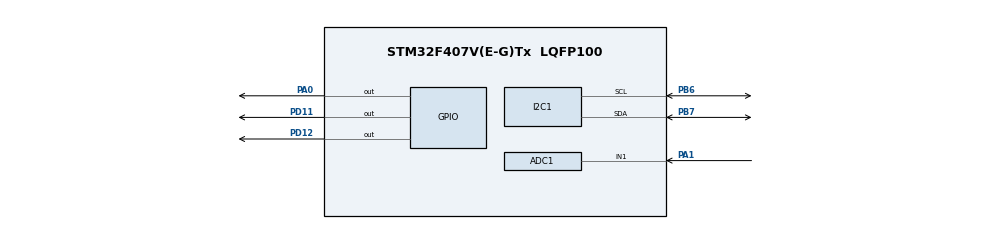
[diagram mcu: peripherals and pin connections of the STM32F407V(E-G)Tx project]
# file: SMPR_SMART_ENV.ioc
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ADC1.Channel-0\#ChannelRegularConversion=ADC_CHANNEL_1
ADC1.NbrOfConversionFlag=1
ADC1.Rank-0\#ChannelRegularConversion=1
ADC1.SamplingTime-0\#ChannelRegularConversion=ADC_SAMPLETIME_3CYCLES
ADC1.master=1
Mcu.Family=STM32F4
Mcu.Name=STM32F407V(E-G)Tx
Mcu.Package=LQFP100
NVIC.ADC_IRQn=true\:0\:0\:false\:false\:true\:true\:true\:true
NVIC.PriorityGroup=NVIC_PRIORITYGROUP_0
PA0-WKUP.PinState=GPIO_PIN_RESET
PA0-WKUP.Signal=GPIO_Output
PA1.Signal=ADCx_IN1
PB6.Mode=I2C
PB6.Signal=I2C1_SCL
PB7.Mode=I2C
PB7.Signal=I2C1_SDA
PD11.PinState=GPIO_PIN_RESET
PD11.Signal=GPIO_Output
PD12.Signal=GPIO_Output
PH0-OSC_IN.Mode=HSE-External-Oscillator
PH0-OSC_IN.Signal=RCC_OSC_IN
PH1-OSC_OUT.Mode=HSE-External-Oscillator
PH1-OSC_OUT.Signal=RCC_OSC_OUT
ProjectManager.HeapSize=0x200
ProjectManager.StackSize=0x400
ProjectManager.TargetToolchain=STM32CubeIDE
RCC.48MHZClocksFreq_Value=14285714.285714285
RCC.AHBFreq_Value=25000000
RCC.APB1CLKDivider=RCC_HCLK_DIV4
RCC.APB1Freq_Value=6250000
RCC.APB1TimFreq_Value=12500000
RCC.APB2CLKDivider=RCC_HCLK_DIV2
RCC.APB2Freq_Value=12500000
RCC.APB2TimFreq_Value=25000000
RCC.CortexFreq_Value=25000000
RCC.HCLKFreq_Value=25000000
RCC.HSE_VALUE=8000000
RCC.HSI_VALUE=16000000
RCC.LSE_VALUE=32768
RCC.PLLM=8
RCC.PLLN=50
RCC.PLLP=RCC_PLLP_DIV4
RCC.PLLQ=7
RCC.SYSCLKFreq_VALUE=25000000
RCC.SYSCLKSource=RCC_SYSCLKSOURCE_PLLCLK
RCC.VCOOutputFreq_Value=100000000
SH.ADCx_IN1.0=ADC1_IN1,IN1
board=STM32F407G-DISC1

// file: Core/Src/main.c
/* USER CODE BEGIN Header */
/**
  ******************************************************************************
  * @file           : main.c
  * @brief          : Main program body
  ******************************************************************************
  * @attention
  *
  * Copyright (c) 2025 STMicroelectronics.
  * All rights reserved.
  *
  * This software is licensed under terms that can be found in the LICENSE file
  * in the root directory of this software component.
  * If no LICENSE file comes with this software, it is provided AS-IS.
  *
  ******************************************************************************
  */
/* USER CODE END Header */
#include "main.h"
#include<string.h>
#include<stdio.h>
#include"DHT11.h"
#include"MQ2.h"
#include"MY_LCD.h"

ADC_HandleTypeDef hadc1;

I2C_HandleTypeDef hi2c1;

void SystemClock_Config(void);
static void MX_GPIO_Init(void);
static void MX_ADC1_Init(void);
static void MX_I2C1_Init(void);

int main(void)
{

  /* USER CODE BEGIN 1 */
	uint8_t temp = 0;
	uint8_t hum = 0;

  /* USER CODE END 1 */

  /* MCU Configuration--------------------------------------------------------*/

  /* Reset of all peripherals, Initializes the Flash interface and the Systick. */
  HAL_Init();

  /* USER CODE BEGIN Init */
 // DHT11_Init();

  /* USER CODE END Init */

  /* Configure the system clock */
  SystemClock_Config();

  /* Initialize all configured peripherals */
  MX_GPIO_Init();
  MX_ADC1_Init();
  MX_I2C1_Init();
  /* USER CODE BEGIN 2 */
  DHT11_Init();
  char str1[60];
  char str2[50];
  int gas;
  if (!lcd16x2_i2c_init(&hi2c1))
  {
	  while(1);
  }

  /* USER CODE END 2 */

  /* Infinite loop */
  while (1)
  {
	  gas=mq2_Read();
	  lcd16x2_i2c_clear();
	  lcd16x2_i2c_setCursor(0,0);
	  lcd16x2_i2c_printf("SmokeD:");
	  lcd16x2_i2c_setCursor(0,8);
	  sprintf(str1, "ADC:%d",gas);
	  lcd16x2_i2c_printf(str1);
	  HAL_Delay(500);

	  HAL_GPIO_WritePin(GPIOD,GPIO_PIN_11|GPIO_PIN_12,GPIO_PIN_RESET);
	  if(gas>200 && gas<500)
	  {
		  HAL_GPIO_WritePin(GPIOD,GPIO_PIN_11,GPIO_PIN_SET);
	  }
	  else if(gas>500 && gas<2000)
	  {
		  HAL_GPIO_WritePin(GPIOD, GPIO_PIN_12,GPIO_PIN_SET);
	  }
	  if (DHT11_Read(&temp,&hum)==0)
	  	  {
	  		  lcd16x2_i2c_clear();
	  		 // lcd16x2_i2c_setCursor(1,0);
	  		 // lcd16x2_i2c_printf("DHT11:");
	  		  lcd16x2_i2c_setCursor(1,0);
	  		  sprintf(str2,"T:=%d c,H:=%d ",temp,hum);
	  		  lcd16x2_i2c_printf(str2);
	  		  HAL_Delay(500);
	  	  }

  }
}

void SystemClock_Config(void)
{
  RCC_OscInitTypeDef RCC_OscInitStruct = {0};
  RCC_ClkInitTypeDef RCC_ClkInitStruct = {0};

  /** Configure the main internal regulator output voltage
  */
  __HAL_RCC_PWR_CLK_ENABLE();
  __HAL_PWR_VOLTAGESCALING_CONFIG(PWR_REGULATOR_VOLTAGE_SCALE1);

  /** Initializes the RCC Oscillators according to the specified parameters
  * in the RCC_OscInitTypeDef structure.
  */
  RCC_OscInitStruct.OscillatorType = RCC_OSCILLATORTYPE_HSE;
  RCC_OscInitStruct.HSEState = RCC_HSE_ON;
  RCC_OscInitStruct.PLL.PLLState = RCC_PLL_ON;
  RCC_OscInitStruct.PLL.PLLSource = RCC_PLLSOURCE_HSE;
  RCC_OscInitStruct.PLL.PLLM = 8;
  RCC_OscInitStruct.PLL.PLLN = 336;
  RCC_OscInitStruct.PLL.PLLP = RCC_PLLP_DIV2;
  RCC_OscInitStruct.PLL.PLLQ = 7;
  if (HAL_RCC_OscConfig(&RCC_OscInitStruct) != HAL_OK)
  {
    Error_Handler();
  }

  /** Initializes the CPU, AHB and APB buses clocks
  */
  RCC_ClkInitStruct.ClockType = RCC_CLOCKTYPE_HCLK|RCC_CLOCKTYPE_SYSCLK
                              |RCC_CLOCKTYPE_PCLK1|RCC_CLOCKTYPE_PCLK2;
  RCC_ClkInitStruct.SYSCLKSource = RCC_SYSCLKSOURCE_PLLCLK;
  RCC_ClkInitStruct.AHBCLKDivider = RCC_SYSCLK_DIV1;
  RCC_ClkInitStruct.APB1CLKDivider = RCC_HCLK_DIV4;
  RCC_ClkInitStruct.APB2CLKDivider = RCC_HCLK_DIV2;

  if (HAL_RCC_ClockConfig(&RCC_ClkInitStruct, FLASH_LATENCY_5) != HAL_OK)
  {
    Error_Handler();
  }
}

static void MX_ADC1_Init(void)
{

  ADC_ChannelConfTypeDef sConfig = {0};

  /** Configure the global features of the ADC (Clock, Resolution, Data Alignment and number of conversion)
  */
  hadc1.Instance = ADC1;
  hadc1.Init.ClockPrescaler = ADC_CLOCK_SYNC_PCLK_DIV4;
  hadc1.Init.Resolution = ADC_RESOLUTION_12B;
  hadc1.Init.ScanConvMode = DISABLE;
  hadc1.Init.ContinuousConvMode = DISABLE;
  hadc1.Init.DiscontinuousConvMode = DISABLE;
  hadc1.Init.ExternalTrigConvEdge = ADC_EXTERNALTRIGCONVEDGE_NONE;
  hadc1.Init.ExternalTrigConv = ADC_SOFTWARE_START;
  hadc1.Init.DataAlign = ADC_DATAALIGN_RIGHT;
  hadc1.Init.NbrOfConversion = 1;
  hadc1.Init.DMAContinuousRequests = DISABLE;
  hadc1.Init.EOCSelection = ADC_EOC_SINGLE_CONV;
  if (HAL_ADC_Init(&hadc1) != HAL_OK)
  {
    Error_Handler();
  }

  /** Configure for the selected ADC regular channel its corresponding rank in the sequencer and its sample time.
  */
  sConfig.Channel = ADC_CHANNEL_1;
  sConfig.Rank = 1;
  sConfig.SamplingTime = ADC_SAMPLETIME_3CYCLES;
  if (HAL_ADC_ConfigChannel(&hadc1, &sConfig) != HAL_OK)
  {
    Error_Handler();
  }

}

static void MX_I2C1_Init(void)
{

  hi2c1.Instance = I2C1;
  hi2c1.Init.ClockSpeed = 100000;
  hi2c1.Init.DutyCycle = I2C_DUTYCYCLE_2;
  hi2c1.Init.OwnAddress1 = 0;
  hi2c1.Init.AddressingMode = I2C_ADDRESSINGMODE_7BIT;
  hi2c1.Init.DualAddressMode = I2C_DUALADDRESS_DISABLE;
  hi2c1.Init.OwnAddress2 = 0;
  hi2c1.Init.GeneralCallMode = I2C_GENERALCALL_DISABLE;
  hi2c1.Init.NoStretchMode = I2C_NOSTRETCH_DISABLE;
  if (HAL_I2C_Init(&hi2c1) != HAL_OK)
  {
    Error_Handler();
  }

}

static void MX_GPIO_Init(void)
{
  GPIO_InitTypeDef GPIO_InitStruct = {0};

  /* GPIO Ports Clock Enable */
  __HAL_RCC_GPIOH_CLK_ENABLE();
  __HAL_RCC_GPIOA_CLK_ENABLE();
  __HAL_RCC_GPIOD_CLK_ENABLE();
  __HAL_RCC_GPIOB_CLK_ENABLE();

  /*Configure GPIO pin Output Level */
  HAL_GPIO_WritePin(GPIOA, GPIO_PIN_0, GPIO_PIN_RESET);

  /*Configure GPIO pin Output Level */
  HAL_GPIO_WritePin(GPIOD, GPIO_PIN_11|GPIO_PIN_12, GPIO_PIN_RESET);

  /*Configure GPIO pin : PA0 */
  GPIO_InitStruct.Pin = GPIO_PIN_0;
  GPIO_InitStruct.Mode = GPIO_MODE_OUTPUT_PP;
  GPIO_InitStruct.Pull = GPIO_NOPULL;
  GPIO_InitStruct.Speed = GPIO_SPEED_FREQ_LOW;
  HAL_GPIO_Init(GPIOA, &GPIO_InitStruct);

  /*Configure GPIO pins : PD11 PD12 */
  GPIO_InitStruct.Pin = GPIO_PIN_11|GPIO_PIN_12;
  GPIO_InitStruct.Mode = GPIO_MODE_OUTPUT_PP;
  GPIO_InitStruct.Pull = GPIO_NOPULL;
  GPIO_InitStruct.Speed = GPIO_SPEED_FREQ_LOW;
  HAL_GPIO_Init(GPIOD, &GPIO_InitStruct);

}

void Error_Handler(void)
{
  __disable_irq();
  while (1)
  {
  }
}
